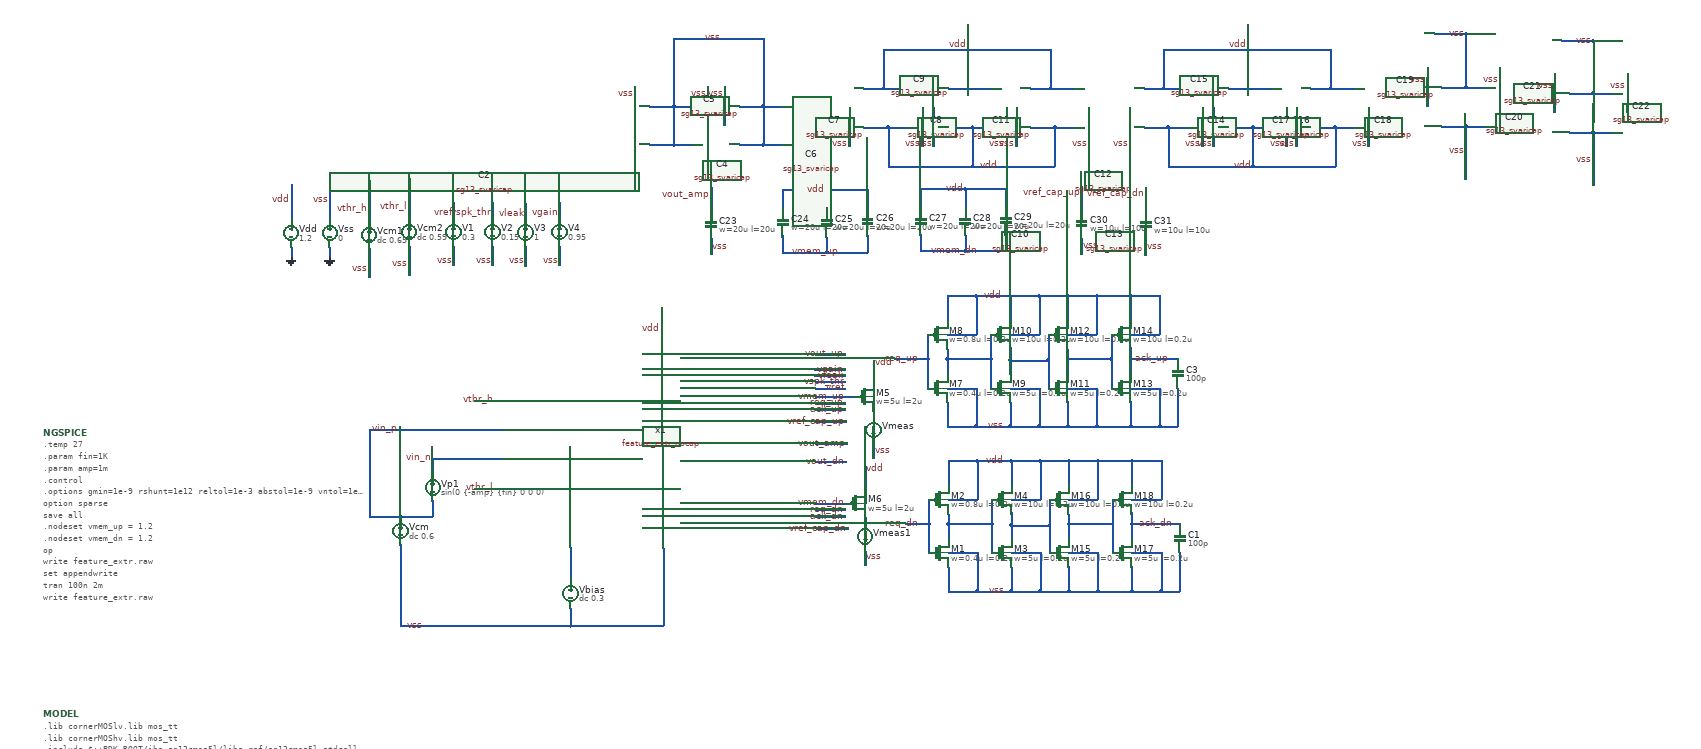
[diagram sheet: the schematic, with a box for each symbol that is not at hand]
v {xschem version=3.4.8RC file_version=1.3}
G {}
K {}
V {}
S {}
F {}
E {}
B 2 2471.25 -692.5 3271.25 -292.5 {flags=graph
y1=0.53
y2=0.74
ypos1=0
ypos2=2
divy=5
subdivy=1
unity=1
x1=0
x2=0.002
divx=5
subdivx=1
xlabmag=1.0
ylabmag=1.0
node="vout_amp
vthr_h
vthr_l
vthr
vint"
dataset=-1
unitx=1
logx=0
logy=0
rawfile=$netlist_dir/feature_extr.raw
sim_type=tran
autoload=1
color="3 7 4 12 9"
hilight_wave=2}
B 2 3291.25 -1107.5 4091.25 -707.5 {flags=graph
y1=0.0018
y2=0.21
ypos1=0
ypos2=2
divy=5
subdivy=1
unity=1
x1=0
x2=0.002
divx=5
subdivx=1
xlabmag=1.0
ylabmag=1.0
node="vout_up
vout_dn"
dataset=-1
unitx=1
logx=0
logy=0
rawfile=$netlist_dir/feature_extr.raw
sim_type=tran
autoload=1
color="4 5"
hilight_wave=1}
B 2 3291.25 -692.5 4091.25 -292.5 {flags=graph
y1=0
y2=0.01
ypos1=0
ypos2=2
divy=5
subdivy=1
unity=1
x1=0
x2=0.002
divx=5
subdivx=1
xlabmag=1.0
ylabmag=1.0
dataset=-1
unitx=1
logx=0
logy=0
sim_type=tran
autoload=1
color="5 4"
node="i(v.x1.vmeas3)
i(v.x1.vmeas1)"
hilight_wave=1}
B 2 2481.25 -222.5 3281.25 177.5 {flags=graph
y1=0.53
y2=0.74
ypos1=0
ypos2=2
divy=5
subdivy=1
unity=1
x1=0
x2=0.002
divx=5
subdivx=1
xlabmag=1.0
ylabmag=1.0
dataset=-1
unitx=1
logx=0
logy=0
rawfile=$netlist_dir/feature_extr.raw
sim_type=tran
autoload=1
color="10 7 12"
node="vout_amp
x1.net6
x1.net5"}
B 2 3303.125 -267.5 4103.125 132.5 {flags=graph
y1=0
y2=0.01
ypos1=0
ypos2=2
divy=5
subdivy=1
unity=1
x1=0
x2=0.002
divx=5
subdivx=1
xlabmag=1.0
ylabmag=1.0
dataset=-1
unitx=1
logx=0
logy=0
sim_type=tran
autoload=1
color="4 6"
node="i(v.x1.vmeas4)
i(v.x1.vmeas2)"
hilight_wave=-1}
B 2 3330 196.25 4130 596.25 {flags=graph
y1=2.2e-09
y2=6.8e-08
ypos1=0
ypos2=2
divy=5
subdivy=1
unity=1
x1=0
x2=0.002
divx=5
subdivx=1
xlabmag=1.0
ylabmag=1.0
node=i(vmeas)
dataset=-1
unitx=1
logx=0
logy=0
rawfile=$netlist_dir/feature_extr.raw
sim_type=tran
autoload=1
color=4
hilight_wave=-1}
B 2 4170 196.25 4970 596.25 {flags=graph
y1=2.1e-09
y2=3.5e-08
ypos1=0
ypos2=2
divy=5
subdivy=1
unity=1
x1=0
x2=0.002
divx=5
subdivx=1
xlabmag=1.0
ylabmag=1.0
dataset=-1
unitx=1
logx=0
logy=0
rawfile=$netlist_dir/feature_extr.raw
sim_type=tran
autoload=1
color=4
node=i(vmeas1)
hilight_wave=-1}
B 2 4108.525390625 -695.302734375 4908.525390625 -295.302734375 {flags=graph
y1=-0.004
y2=1.3
ypos1=0
ypos2=2
divy=5
subdivy=1
unity=1
x1=0
x2=0.002
divx=5
subdivx=1
xlabmag=1.0
ylabmag=1.0
node="req_up
ack_up"
dataset=-1
unitx=1
logx=0
logy=0
rawfile=$netlist_dir/feature_extr.raw
sim_type=tran
autoload=1
color="5 4"
hcursor2_y=-0.86477319
hilight_wave=0}
B 2 2471.25 -1107.5 3271.25 -707.5 {flags=graph
y1=0.59
y2=0.61
ypos1=0
ypos2=2
divy=5
subdivy=1
unity=1
x1=0
x2=0.002
divx=5
subdivx=1
xlabmag=1.0
ylabmag=1.0
node="vin_p
vin_n"
dataset=-1
unitx=1
logx=0
logy=0
rawfile=$netlist_dir/feature_extr.raw
sim_type=tran
autoload=1
color="6 3"}
B 2 4108.2275390625 -1108.84765625 4908.2275390625 -708.84765625 {flags=graph
y1=0.94
y2=1.3
ypos1=0
ypos2=2
divy=5
subdivy=1
unity=1
x1=0
x2=0.002
divx=5
subdivx=1
xlabmag=1.0
ylabmag=1.0
node="vmem_up
vmem_dn"
dataset=-1
unitx=1
logx=0
logy=0
rawfile=$netlist_dir/feature_extr.raw
sim_type=tran
autoload=1
color="5 4"
hilight_wave=-1}
B 2 4928.2275390625 -1108.84765625 5728.2275390625 -708.84765625 {flags=graph
y1=0.959568
y2=1.558848
ypos1=0
ypos2=2
divy=5
subdivy=1
unity=1
x1=0
x2=0.002
divx=5
subdivx=1
xlabmag=1.0
ylabmag=1.0
dataset=-1
unitx=1
logx=0
logy=0
rawfile=$netlist_dir/feature_extr.raw
sim_type=tran
autoload=1
hilight_wave=1
color="5 4"
node="x1.x5.vmem_d
x1.x7.vmem_d"}
B 2 4108.525390625 -265.302734375 4908.525390625 134.697265625 {flags=graph
y1=-0.0036
y2=1.3
ypos1=0
ypos2=2
divy=5
subdivy=1
unity=1
x1=0
x2=0.002
divx=5
subdivx=1
xlabmag=1.0
ylabmag=1.0
node="req_dn
ack_dn"
dataset=-1
unitx=1
logx=0
logy=0
rawfile=$netlist_dir/feature_extr.raw
sim_type=tran
autoload=1
color="4 10"
hcursor2_y=-0.86477319
hilight_wave=-1}
N 510 -1102.5 510 -1082.5 {
lab=GND}
N 590 -1102.5 590 -1082.5 {
lab=GND}
N 672.5 -727.5 947.5 -727.5 {
lab=vin_p}
N 672.5 -727.5 672.5 -547.5 {lab=vin_p}
N 736.25 -547.5 802.5 -547.5 {lab=vin_p}
N 671.25 -1240 671.25 -1157.5 {lab=vthr_h}
N 671.25 -1100 671.25 -1040 {lab=vss}
N 753.75 -1103.75 753.75 -1043.75 {lab=vss}
N 510 -1232.5 510 -1162.5 {lab=vdd}
N 590 -1232.5 590 -1162.5 {lab=vss}
N 1278.75 -482.5 1278.75 -322.5 {lab=vss}
N 888.75 -787.5 946.25 -787.5 {lab=vthr_h}
N 888.75 -606.25 947.5 -606.25 {lab=vthr_l}
N 1273.75 -977.5 1273.75 -925 {lab=vdd}
N 1591.25 -882.5 1653.75 -882.5 {lab=vout_up}
N 1591.25 -697.5 1657.5 -697.5 {lab=vout_amp}
N 1591.25 -825 1653.75 -825 {lab=vspk_thr}
N 1591.25 -812.5 1653.75 -812.5 {lab=vref}
N 1591.25 -795 1671.25 -795 {lab=vmem_up}
N 1591.25 -781.25 1653.75 -781.25 {lab=req_up}
N 1591.25 -767.5 1653.75 -767.5 {lab=ack_up}
N 1591.25 -575 1653.75 -575 {lab=vmem_dn}
N 1591.25 -561.25 1653.75 -561.25 {lab=req_dn}
N 1591.25 -547.5 1653.75 -547.5 {lab=ack_dn}
N 2301.25 -733.75 2338.75 -733.75 {lab=vss}
N 2338.75 -812.5 2338.75 -733.75 {lab=vss}
N 1865 -532.5 1865 -502.5 {lab=#net1}
N 1825 -532.5 1825 -472.5 {lab=req_dn}
N 1865 -662.5 1865 -612.5 {lab=vdd}
N 1865 -472.5 1925 -472.5 {lab=vss}
N 1865 -582.5 1925 -582.5 {lab=vdd}
N 1925 -662.5 1925 -582.5 {lab=vdd}
N 1865 -662.5 1925 -662.5 {lab=vdd}
N 1865 -532.5 1955 -532.5 {lab=#net1}
N 1865 -552.5 1865 -532.5 {lab=#net1}
N 1955 -532.5 1955 -472.5 {lab=#net1}
N 1955 -582.5 1955 -532.5 {lab=#net1}
N 1995 -662.5 1995 -612.5 {lab=vdd}
N 1995 -472.5 2055 -472.5 {lab=vss}
N 1995 -582.5 2055 -582.5 {lab=vdd}
N 2055 -662.5 2055 -582.5 {lab=vdd}
N 1995 -662.5 2055 -662.5 {lab=vdd}
N 1925 -662.5 1995 -662.5 {lab=vdd}
N 1777.5 -532.5 1825 -532.5 {lab=req_dn}
N 1825 -582.5 1825 -532.5 {lab=req_dn}
N 2055 -472.5 2055 -393.75 {lab=vss}
N 1865 -442.5 1865 -393.75 {lab=vss}
N 1925 -472.5 1925 -393.75 {lab=vss}
N 1995 -442.5 1995 -393.75 {lab=vss}
N 2303.75 -393.75 2342.5 -393.75 {lab=vss}
N 1865 -393.75 1925 -393.75 {lab=vss}
N 1925 -393.75 1995 -393.75 {lab=vss}
N 1995 -393.75 2055 -393.75 {lab=vss}
N 2342.5 -472.5 2342.5 -393.75 {lab=vss}
N 753.75 -1243.75 753.75 -1163.75 {lab=vthr_l}
N 845.390625 -1194.296875 845.390625 -1164.296875 {lab=vref}
N 845.390625 -1104.296875 845.390625 -1064.296875 {lab=vss}
N 802.5 -667.5 802.5 -637.5 {lab=vin_n}
N 802.5 -667.5 946.25 -667.5 {lab=vin_n}
N 1591.25 -660 1655 -660 {lab=vout_dn}
N 1086.25 -322.5 1278.75 -322.5 {lab=vss}
N 1086.25 -483.75 1086.25 -418.75 {lab=#net2}
N 1086.25 -358.75 1086.25 -322.5 {lab=vss}
N 736.25 -322.5 1086.25 -322.5 {lab=vss}
N 1711.25 -870 1711.25 -795 {lab=vdd}
N 1693.75 -650 1693.75 -575 {lab=vdd}
N 1711.25 -766.25 1711.25 -755 {lab=#net3}
N 1711.25 -696.25 1711.25 -667.5 {lab=vss}
N 1693.75 -546.25 1693.75 -535 {lab=#net4}
N 1693.75 -476.25 1693.75 -447.5 {lab=vss}
N 925.390625 -1194.296875 925.390625 -1164.296875 {lab=vspk_thr}
N 925.390625 -1104.296875 925.390625 -1064.296875 {lab=vss}
N 993.515625 -1193.671875 993.515625 -1163.671875 {lab=vleak}
N 993.515625 -1103.671875 993.515625 -1063.671875 {lab=vss}
N 1588.4375 -837.5 1654.0625 -837.5 {lab=vleak}
N 1063.59375 -1194.375 1063.59375 -1164.375 {lab=vgain}
N 1063.59375 -1104.375 1063.59375 -1064.375 {lab=vss}
N 1588.4375 -850 1654.0625 -850 {lab=vgain}
N 1995 -530 1995 -499.921875 {lab=#net5}
N 2241.25 -872.5 2338.75 -872.5 {lab=ack_up}
N 2113.75 -532.5 2113.75 -502.5 {lab=#net6}
N 2113.75 -662.5 2113.75 -612.5 {lab=vdd}
N 2113.75 -472.5 2173.75 -472.5 {lab=vss}
N 2113.75 -582.5 2173.75 -582.5 {lab=vdd}
N 2173.75 -662.5 2173.75 -582.5 {lab=vdd}
N 2113.75 -532.5 2203.75 -532.5 {lab=#net6}
N 2113.75 -552.5 2113.75 -532.5 {lab=#net6}
N 2203.75 -532.5 2203.75 -472.5 {lab=#net6}
N 2203.75 -582.5 2203.75 -532.5 {lab=#net6}
N 2243.75 -662.5 2243.75 -612.5 {lab=vdd}
N 2243.75 -472.5 2303.75 -472.5 {lab=vss}
N 2243.75 -582.5 2303.75 -582.5 {lab=vdd}
N 2303.75 -662.5 2303.75 -582.5 {lab=vdd}
N 2243.75 -662.5 2303.75 -662.5 {lab=vdd}
N 2173.75 -662.5 2243.75 -662.5 {lab=vdd}
N 2113.75 -662.5 2173.75 -662.5 {lab=vdd}
N 2113.75 -443.75 2113.75 -393.75 {lab=vss}
N 2243.75 -443.75 2243.75 -393.75 {lab=vss}
N 2173.75 -393.75 2243.75 -393.75 {lab=vss}
N 2073.75 -530 2073.75 -472.5 {lab=#net5}
N 2173.75 -472.5 2173.75 -393.75 {lab=vss}
N 2113.75 -393.75 2173.75 -393.75 {lab=vss}
N 2303.75 -472.5 2303.75 -393.75 {lab=vss}
N 2243.75 -393.75 2303.75 -393.75 {lab=vss}
N 2243.75 -532.5 2243.75 -499.765625 {lab=ack_dn}
N 2055 -393.75 2113.75 -393.75 {lab=vss}
N 2055 -662.5 2113.75 -662.5 {lab=vdd}
N 1995 -530 2073.75 -530 {lab=#net5}
N 1995 -555.078125 1995 -530 {lab=#net5}
N 2073.75 -582.5 2073.75 -530 {lab=#net5}
N 2243.75 -532.5 2342.5 -532.5 {lab=ack_dn}
N 2243.75 -555.078125 2243.75 -532.5 {lab=ack_dn}
N 1862.5 -872.5 1862.5 -842.5 {lab=#net7}
N 1862.5 -1002.5 1862.5 -952.5 {lab=vdd}
N 1862.5 -812.5 1922.5 -812.5 {lab=vss}
N 1862.5 -922.5 1922.5 -922.5 {lab=vdd}
N 1922.5 -1002.5 1922.5 -922.5 {lab=vdd}
N 1862.5 -1002.5 1922.5 -1002.5 {lab=vdd}
N 1862.5 -872.5 1952.5 -872.5 {lab=#net7}
N 1862.5 -892.5 1862.5 -872.5 {lab=#net7}
N 1952.5 -872.5 1952.5 -812.5 {lab=#net7}
N 1952.5 -922.5 1952.5 -872.5 {lab=#net7}
N 1992.5 -1002.5 1992.5 -952.5 {lab=vdd}
N 1992.5 -812.5 2052.5 -812.5 {lab=vss}
N 1992.5 -922.5 2052.5 -922.5 {lab=vdd}
N 2052.5 -1002.5 2052.5 -922.5 {lab=vdd}
N 1992.5 -1002.5 2052.5 -1002.5 {lab=vdd}
N 1922.5 -1002.5 1992.5 -1002.5 {lab=vdd}
N 1822.5 -872.5 1822.5 -812.5 {lab=req_up}
N 2052.5 -812.5 2052.5 -733.75 {lab=vss}
N 1862.5 -782.5 1862.5 -733.75 {lab=vss}
N 1922.5 -812.5 1922.5 -733.75 {lab=vss}
N 1992.5 -782.5 1992.5 -733.75 {lab=vss}
N 1862.5 -733.75 1922.5 -733.75 {lab=vss}
N 1922.5 -733.75 1992.5 -733.75 {lab=vss}
N 1992.5 -733.75 2052.5 -733.75 {lab=vss}
N 1992.5 -870 1992.5 -839.921875 {lab=#net8}
N 2111.25 -872.5 2111.25 -842.5 {lab=#net9}
N 2111.25 -1002.5 2111.25 -952.5 {lab=vdd}
N 2111.25 -812.5 2171.25 -812.5 {lab=vss}
N 2111.25 -922.5 2171.25 -922.5 {lab=vdd}
N 2171.25 -1002.5 2171.25 -922.5 {lab=vdd}
N 2111.25 -872.5 2201.25 -872.5 {lab=#net9}
N 2111.25 -892.5 2111.25 -872.5 {lab=#net9}
N 2201.25 -872.5 2201.25 -812.5 {lab=#net9}
N 2201.25 -922.5 2201.25 -872.5 {lab=#net9}
N 2241.25 -1002.5 2241.25 -952.5 {lab=vdd}
N 2241.25 -812.5 2301.25 -812.5 {lab=vss}
N 2241.25 -922.5 2301.25 -922.5 {lab=vdd}
N 2301.25 -1002.5 2301.25 -922.5 {lab=vdd}
N 2241.25 -1002.5 2301.25 -1002.5 {lab=vdd}
N 2171.25 -1002.5 2241.25 -1002.5 {lab=vdd}
N 2111.25 -1002.5 2171.25 -1002.5 {lab=vdd}
N 2111.25 -783.75 2111.25 -733.75 {lab=vss}
N 2241.25 -783.75 2241.25 -733.75 {lab=vss}
N 2171.25 -733.75 2241.25 -733.75 {lab=vss}
N 2071.25 -870 2071.25 -812.5 {lab=#net8}
N 2171.25 -812.5 2171.25 -733.75 {lab=vss}
N 2111.25 -733.75 2171.25 -733.75 {lab=vss}
N 2301.25 -812.5 2301.25 -733.75 {lab=vss}
N 2241.25 -733.75 2301.25 -733.75 {lab=vss}
N 2052.5 -733.75 2111.25 -733.75 {lab=vss}
N 2052.5 -1002.5 2111.25 -1002.5 {lab=vdd}
N 1992.5 -870 2071.25 -870 {lab=#net8}
N 1992.5 -895.078125 1992.5 -870 {lab=#net8}
N 2071.25 -922.5 2071.25 -870 {lab=#net8}
N 2241.25 -872.5 2241.25 -839.765625 {lab=ack_up}
N 2241.25 -895.078125 2241.25 -872.5 {lab=ack_up}
N 1755 -872.5 1822.5 -872.5 {lab=req_up}
N 1822.5 -922.5 1822.5 -872.5 {lab=req_up}
N 736.25 -490 736.25 -322.5 {lab=vss}
N 802.5 -581.25 802.5 -547.5 {lab=vin_p}
N 736.25 -547.5 736.25 -543.75 {lab=vin_p}
N 672.5 -547.5 736.25 -547.5 {lab=vin_p}
N 1590 -742.5 1656.25 -742.5 {lab=vref_cap_up}
N 1592.5 -522.5 1658.75 -522.5 {lab=vref_cap_dn}
N 1298.75 -1393.75 1338.75 -1393.75 {lab=vss}
N 1298.75 -1313.75 1338.75 -1313.75 {lab=vss}
N 1298.75 -1393.75 1298.75 -1313.75 {lab=vss}
N 1248.75 -1313.75 1298.75 -1313.75 {lab=vss}
N 1248.75 -1393.75 1298.75 -1393.75 {lab=vss}
N 1218.75 -1433.75 1218.75 -1353.75 {lab=vss}
N 1368.75 -1433.75 1368.75 -1353.75 {lab=vss}
N 1298.75 -1533.75 1298.75 -1393.75 {lab=vss}
N 1483.75 -1393.75 1523.75 -1393.75 {lab=vss}
N 1483.75 -1313.75 1523.75 -1313.75 {lab=vss}
N 1483.75 -1393.75 1483.75 -1313.75 {lab=vss}
N 1433.75 -1313.75 1483.75 -1313.75 {lab=vss}
N 1433.75 -1393.75 1483.75 -1393.75 {lab=vss}
N 1403.75 -1433.75 1403.75 -1353.75 {lab=vss}
N 1483.75 -1533.75 1483.75 -1393.75 {lab=vss}
N 1298.75 -1533.75 1483.75 -1533.75 {lab=vss}
N 1741.25 -1350 1781.25 -1350 {lab=vdd}
N 1741.25 -1350 1741.25 -1270 {lab=vdd}
N 1691.25 -1350 1741.25 -1350 {lab=vdd}
N 1731.25 -1430 1781.25 -1430 {lab=vdd}
N 1661.25 -1390 1661.25 -1310 {lab=vss}
N 1811.25 -1390 1811.25 -1310 {lab=vss}
N 1731.25 -1510 1731.25 -1430 {lab=vdd}
N 1691.25 -1430 1731.25 -1430 {lab=vdd}
N 1915 -1350 1955 -1350 {lab=vdd}
N 1915 -1350 1915 -1270 {lab=vdd}
N 1865 -1350 1915 -1350 {lab=vdd}
N 1905 -1430 1955 -1430 {lab=vdd}
N 1835 -1390 1835 -1310 {lab=vss}
N 1985 -1390 1985 -1310 {lab=vss}
N 1905 -1510 1905 -1430 {lab=vdd}
N 1865 -1430 1905 -1430 {lab=vdd}
N 2085 -1350 2125 -1350 {lab=vdd}
N 2085 -1350 2085 -1270 {lab=vdd}
N 2035 -1350 2085 -1350 {lab=vdd}
N 2075 -1430 2125 -1430 {lab=vdd}
N 2005 -1390 2005 -1310 {lab=vss}
N 2155 -1390 2155 -1310 {lab=vss}
N 2075 -1510 2075 -1430 {lab=vdd}
N 2035 -1430 2075 -1430 {lab=vdd}
N 1905 -1510 2075 -1510 {lab=vdd}
N 1731.25 -1510 1905 -1510 {lab=vdd}
N 2318.75 -1350 2358.75 -1350 {lab=vdd}
N 2318.75 -1350 2318.75 -1270 {lab=vdd}
N 2268.75 -1350 2318.75 -1350 {lab=vdd}
N 2308.75 -1430 2358.75 -1430 {lab=vdd}
N 2238.75 -1390 2238.75 -1310 {lab=vss}
N 2388.75 -1390 2388.75 -1310 {lab=vss}
N 2308.75 -1510 2308.75 -1430 {lab=vdd}
N 2268.75 -1430 2308.75 -1430 {lab=vdd}
N 2492.5 -1350 2532.5 -1350 {lab=vdd}
N 2492.5 -1350 2492.5 -1270 {lab=vdd}
N 2442.5 -1350 2492.5 -1350 {lab=vdd}
N 2482.5 -1430 2532.5 -1430 {lab=vdd}
N 2412.5 -1390 2412.5 -1310 {lab=vss}
N 2562.5 -1390 2562.5 -1310 {lab=vss}
N 2482.5 -1510 2482.5 -1430 {lab=vdd}
N 2442.5 -1430 2482.5 -1430 {lab=vdd}
N 2662.5 -1350 2702.5 -1350 {lab=vdd}
N 2662.5 -1350 2662.5 -1270 {lab=vdd}
N 2612.5 -1350 2662.5 -1350 {lab=vdd}
N 2652.5 -1430 2702.5 -1430 {lab=vdd}
N 2582.5 -1390 2582.5 -1310 {lab=vss}
N 2732.5 -1390 2732.5 -1310 {lab=vss}
N 2652.5 -1510 2652.5 -1430 {lab=vdd}
N 2612.5 -1430 2652.5 -1430 {lab=vdd}
N 2482.5 -1510 2652.5 -1510 {lab=vdd}
N 2308.75 -1510 2482.5 -1510 {lab=vdd}
N 1905 -1562.5 1905 -1510 {lab=vdd}
N 2482.5 -1562.5 2482.5 -1510 {lab=vdd}
N 1915 -1270 2085 -1270 {lab=vdd}
N 2492.5 -1270 2662.5 -1270 {lab=vdd}
N 2318.75 -1270 2492.5 -1270 {lab=vdd}
N 2932.5 -1432.5 2972.5 -1432.5 {lab=vss}
N 2932.5 -1352.5 2972.5 -1352.5 {lab=vss}
N 2882.5 -1432.5 2932.5 -1432.5 {lab=vss}
N 2852.5 -1472.5 2852.5 -1392.5 {lab=vss}
N 3002.5 -1472.5 3002.5 -1392.5 {lab=vss}
N 2932.5 -1542.5 2932.5 -1432.5 {lab=vss}
N 2932.5 -1352.5 2932.5 -1242.5 {lab=vss}
N 2882.5 -1352.5 2932.5 -1352.5 {lab=vss}
N 1741.25 -1270 1915 -1270 {lab=vdd}
N 3195 -1420 3235 -1420 {lab=vss}
N 3195 -1340 3235 -1340 {lab=vss}
N 3145 -1420 3195 -1420 {lab=vss}
N 3115 -1460 3115 -1380 {lab=vss}
N 3265 -1460 3265 -1380 {lab=vss}
N 3195 -1528.75 3195 -1420 {lab=vss}
N 3195 -1340 3195 -1230 {lab=vss}
N 3145 -1340 3195 -1340 {lab=vss}
N 2932.5 -1542.5 2933.75 -1542.5 {lab=vss}
N 2867.5 -1542.5 2932.5 -1542.5 {lab=vss}
N 3195 -1528.75 3196.25 -1528.75 {lab=vss}
N 3130 -1528.75 3195 -1528.75 {lab=vss}
N 3195 -1530 3195 -1528.75 {lab=vss}
N 1376.25 -1226.25 1376.25 -1180 {lab=vout_amp}
N 1376.25 -1120 1376.25 -1087.5 {lab=vss}
N 1523.75 -1126.25 1523.75 -1092.5 {lab=vmem_up}
N 1698.75 -1126.25 1698.75 -1092.5 {lab=vmem_up}
N 1615 -1092.5 1698.75 -1092.5 {lab=vmem_up}
N 1615 -1123.75 1615 -1092.5 {lab=vmem_up}
N 1523.75 -1092.5 1615 -1092.5 {lab=vmem_up}
N 1523.75 -1221.25 1523.75 -1183.75 {lab=vdd}
N 1698.75 -1221.25 1698.75 -1185 {lab=vdd}
N 1615 -1221.25 1698.75 -1221.25 {lab=vdd}
N 1615 -1221.25 1615 -1183.75 {lab=vdd}
N 1523.75 -1221.25 1615 -1221.25 {lab=vdd}
N 1808.75 -1128.75 1808.75 -1095 {lab=vmem_dn}
N 1983.75 -1128.75 1983.75 -1095 {lab=vmem_dn}
N 1900 -1095 1983.75 -1095 {lab=vmem_dn}
N 1900 -1126.25 1900 -1095 {lab=vmem_dn}
N 1808.75 -1095 1900 -1095 {lab=vmem_dn}
N 1808.75 -1223.75 1808.75 -1186.25 {lab=vdd}
N 1983.75 -1223.75 1983.75 -1187.5 {lab=vdd}
N 1900 -1223.75 1983.75 -1223.75 {lab=vdd}
N 1900 -1223.75 1900 -1186.25 {lab=vdd}
N 1808.75 -1223.75 1900 -1223.75 {lab=vdd}
N 2140 -1227.5 2140 -1181.25 {lab=vref_cap_up}
N 2140 -1121.25 2140 -1088.75 {lab=vss}
N 2272.5 -1225 2272.5 -1178.75 {lab=vref_cap_dn}
N 2272.5 -1118.75 2272.5 -1086.25 {lab=vss}
C {devices/vsource.sym} 510 -1132.5 0 0 {name=Vdd value=1.2}
C {devices/gnd.sym} 510 -1082.5 0 0 {name=l3 lab=GND}
C {devices/launcher.sym} 560 -140 0 0 {name=h2
descr="simulate" 
tclcommand="xschem save; xschem netlist; xschem simulate"
}
C {devices/launcher.sym} 800 -140 0 0 {name=h3
descr="annotate OP" 
tclcommand="set show_hidden_texts 1; xschem annotate_op"
}
C {devices/vsource.sym} 590 -1132.5 0 0 {name=Vss value=0}
C {devices/gnd.sym} 590 -1082.5 0 0 {name=l1 lab=GND}
C {devices/vsource.sym} 736.25 -517.5 0 0 {name=Vcm value="dc 0.6"}
C {devices/lab_wire.sym} 732.5 -727.5 0 0 {name=p4 sig_type=std_logic lab=vin_p}
C {devices/lab_wire.sym} 802.5 -667.5 0 0 {name=p7 sig_type=std_logic lab=vin_n}
C {devices/vsource.sym} 802.5 -607.5 0 0 {name=Vp1 value="sin(0 \{-amp\} \{fin\} 0 0 0)"}
C {devices/code_shown.sym} 0 -720 0 0 {name=NGSPICE only_toplevel=true 
value="
.temp 27
.param fin=1K
.param amp=1m
.control
.options gmin=1e-9 rshunt=1e12 reltol=1e-3 abstol=1e-9 vntol=1e-6

option sparse
save all

.nodeset vmem_up = 1.2
.nodeset vmem_dn = 1.2
op
write feature_extr.raw
set appendwrite

tran 100n 2m
write feature_extr.raw
wrdata amplification.csv vin_p vin_n vout_amp
wrdata comparison.csv vout_up vout_dn vthr_h vthr_l i(v.x1.vmeas1) i(v.x1.vmeas3)
wrdata event_conversion.csv req_up req_dn vmem_up vmem_dn


plot v(req_up) v(req_dn)
plot v(vmem_up) v(vmem_dn)


.endc
"}
C {devices/code_shown.sym} 0 -140 0 0 {name=MODEL only_toplevel=true
format="tcleval( @value )"
value="
.lib cornerMOSlv.lib mos_tt
.lib cornerMOShv.lib mos_tt
.include $::PDK_ROOT/ihp-sg13cmos5l/libs.ref/sg13cmos5l_stdcell/spice/sg13cmos5l_stdcell.spice
.include $::PDK_ROOT/ihp-sg13cmos5l/libs.tech/ngspice/models/cap_mfringe.lib
"}
C {devices/title.sym} 160 0 0 0 {name=l5 author="(c) 2024-2025 Harald Pretl, Apache-2.0 license"}
C {devices/vsource.sym} 671.25 -1127.5 0 0 {name=Vcm1 value="dc 0.65"}
C {devices/vsource.sym} 753.75 -1133.75 0 0 {name=Vcm2 value="dc 0.59"}
C {devices/lab_wire.sym} 1806.25 -872.5 0 0 {name=p32 sig_type=std_logic lab=req_up}
C {capa.sym} 2338.75 -842.5 0 0 {name=C3
m=1
value=100p
footprint=1206
device="ceramic capacitor"}
C {lab_wire.sym} 931.25 -787.5 0 0 {name=p6 sig_type=std_logic lab=vthr_h}
C {lab_wire.sym} 931.25 -606.25 0 0 {name=p8 sig_type=std_logic lab=vthr_l}
C {lab_wire.sym} 1273.75 -935 1 0 {name=p9 sig_type=std_logic lab=vdd}
C {lab_wire.sym} 1652.5 -882.5 0 0 {name=p11 sig_type=std_logic lab=vout_up}
C {lab_wire.sym} 1656.25 -697.5 0 0 {name=p12 sig_type=std_logic lab=vout_amp}
C {lab_wire.sym} 1655 -660 0 0 {name=p13 sig_type=std_logic lab=vout_dn}
C {lab_wire.sym} 1653.75 -825 0 0 {name=p16 sig_type=std_logic lab=vspk_thr}
C {lab_wire.sym} 1653.75 -812.5 0 0 {name=p19 sig_type=std_logic lab=vref}
C {lab_wire.sym} 1652.5 -781.25 0 0 {name=p20 sig_type=std_logic lab=req_up}
C {lab_wire.sym} 1653.75 -795 0 0 {name=p22 sig_type=std_logic lab=vmem_up}
C {lab_wire.sym} 1652.5 -767.5 0 0 {name=p23 sig_type=std_logic lab=ack_up}
C {lab_wire.sym} 1652.5 -561.25 0 0 {name=p24 sig_type=std_logic lab=req_dn}
C {lab_wire.sym} 1653.75 -575 0 0 {name=p25 sig_type=std_logic lab=vmem_dn}
C {lab_wire.sym} 1652.5 -547.5 0 0 {name=p26 sig_type=std_logic lab=ack_dn}
C {sg13g2_pr/sg13_lv_nmos.sym} 1845 -472.5 0 0 {name=M1
l=0.2u
w=0.4u
ng=1
m=1
model=sg13_lv_nmos
spiceprefix=X
}
C {sg13g2_pr/sg13_lv_pmos.sym} 1845 -582.5 0 0 {name=M2
l=0.2u
w=0.8u
ng=1
m=1
model=sg13_lv_pmos
spiceprefix=X
}
C {sg13g2_pr/sg13_lv_nmos.sym} 1975 -472.5 0 0 {name=M3
l=0.2u
w=5u
ng=1
m=1
model=sg13_lv_nmos
spiceprefix=X
}
C {sg13g2_pr/sg13_lv_pmos.sym} 1975 -582.5 0 0 {name=M4
l=0.2u
w=10u
ng=1
m=1
model=sg13_lv_pmos
spiceprefix=X
}
C {devices/lab_wire.sym} 1807.5 -532.5 0 0 {name=p29 sig_type=std_logic lab=req_dn}
C {capa.sym} 2342.5 -502.5 0 0 {name=C1
m=1
value=100p
footprint=1206
device="ceramic capacitor"}
C {vsource.sym} 845.390625 -1134.296875 0 0 {name=V1 value=0.3 savecurrent=false}
C {devices/lab_wire.sym} 845.390625 -1173.046875 1 0 {name=p36 sig_type=std_logic lab=vref}
C {noconn.sym} 1652.5 -882.5 2 0 {name=l2}
C {noconn.sym} 1655 -660 2 0 {name=l7}
C {devices/vsource.sym} 1086.25 -388.75 0 0 {name=Vbias value="dc 0.3"}
C {lab_wire.sym} 510 -1200 1 0 {name=p1 sig_type=std_logic lab=vdd}
C {lab_wire.sym} 590 -1200 1 0 {name=p2 sig_type=std_logic lab=vss}
C {lab_wire.sym} 671.25 -1058.75 1 0 {name=p5 sig_type=std_logic lab=vss}
C {lab_wire.sym} 753.75 -1067.5 1 0 {name=p17 sig_type=std_logic lab=vss}
C {lab_wire.sym} 671.25 -1182.5 1 0 {name=p18 sig_type=std_logic lab=vthr_h}
C {lab_wire.sym} 753.75 -1185 1 0 {name=p10 sig_type=std_logic lab=vthr_l}
C {lab_wire.sym} 746.25 -322.5 2 0 {name=p21 sig_type=std_logic lab=vss}
C {lab_wire.sym} 1940 -662.5 2 0 {name=p27 sig_type=std_logic lab=vdd}
C {lab_wire.sym} 1947.5 -393.75 2 0 {name=p31 sig_type=std_logic lab=vss}
C {lab_wire.sym} 845.390625 -1074.296875 1 0 {name=p38 sig_type=std_logic lab=vss}
C {sg13cmos5l_pr/sg13_lv_pmos.sym} 1691.25 -795 0 0 {name=M5
l=2u
w=5u
ng=4
m=2
model=sg13_lv_pmos
spiceprefix=X
}
C {sg13cmos5l_pr/sg13_lv_pmos.sym} 1673.75 -575 0 0 {name=M6
l=2u
w=5u
ng=4
m=2
model=sg13_lv_pmos
spiceprefix=X
}
C {lab_wire.sym} 1711.25 -863.75 2 0 {name=p39 sig_type=std_logic lab=vdd}
C {lab_wire.sym} 1693.75 -645 2 0 {name=p41 sig_type=std_logic lab=vdd}
C {ammeter.sym} 1711.25 -726.25 0 0 {name=Vmeas savecurrent=true spice_ignore=0}
C {lab_wire.sym} 1711.25 -683.75 2 0 {name=p42 sig_type=std_logic lab=vss}
C {ammeter.sym} 1693.75 -506.25 0 0 {name=Vmeas1 savecurrent=true spice_ignore=0}
C {lab_wire.sym} 1693.75 -463.75 2 0 {name=p43 sig_type=std_logic lab=vss}
C {vsource.sym} 925.390625 -1134.296875 0 0 {name=V2 value=0.15 avecurrent=false}
C {devices/lab_wire.sym} 925.390625 -1173.046875 1 0 {name=p44 sig_type=std_logic lab=vspk_thr}
C {lab_wire.sym} 925.390625 -1074.296875 1 0 {name=p45 sig_type=std_logic lab=vss}
C {vsource.sym} 993.515625 -1133.671875 0 0 {name=V3 value=1 savecurrent=false}
C {devices/lab_wire.sym} 993.515625 -1172.421875 1 0 {name=p40 sig_type=std_logic lab=vleak}
C {lab_wire.sym} 993.515625 -1073.671875 1 0 {name=p46 sig_type=std_logic lab=vss}
C {feature_extr_nocap.sym} 1272.5 -702.5 0 0 {name=x1}
C {lab_wire.sym} 1653.125 -837.5 0 0 {name=p15 sig_type=std_logic lab=vleak}
C {vsource.sym} 1063.59375 -1134.375 0 0 {name=V4 value=0.95 savecurrent=false}
C {devices/lab_wire.sym} 1063.59375 -1173.125 1 0 {name=p33 sig_type=std_logic lab=vgain}
C {lab_wire.sym} 1063.59375 -1074.375 1 0 {name=p34 sig_type=std_logic lab=vss}
C {lab_wire.sym} 1653.125 -850 0 0 {name=p35 sig_type=std_logic lab=vgain}
C {sg13g2_pr/sg13_lv_nmos.sym} 2093.75 -472.5 0 0 {name=M15
l=0.2u
w=5u
ng=1
m=1
model=sg13_lv_nmos
spiceprefix=X
}
C {sg13g2_pr/sg13_lv_pmos.sym} 2093.75 -582.5 0 0 {name=M16
l=0.2u
w=10u
ng=1
m=1
model=sg13_lv_pmos
spiceprefix=X
}
C {sg13g2_pr/sg13_lv_nmos.sym} 2223.75 -472.5 0 0 {name=M17
l=0.2u
w=5u
ng=1
m=1
model=sg13_lv_nmos
spiceprefix=X
}
C {sg13g2_pr/sg13_lv_pmos.sym} 2223.75 -582.5 0 0 {name=M18
l=0.2u
w=10u
ng=1
m=1
model=sg13_lv_pmos
spiceprefix=X
}
C {lab_wire.sym} 2331.25 -532.5 0 0 {name=p37 sig_type=std_logic lab=ack_dn}
C {lab_wire.sym} 2322.5 -872.5 0 0 {name=p47 sig_type=std_logic lab=ack_up}
C {sg13g2_pr/sg13_lv_nmos.sym} 1842.5 -812.5 0 0 {name=M7
l=0.2u
w=0.4u
ng=1
m=1
model=sg13_lv_nmos
spiceprefix=X
}
C {sg13g2_pr/sg13_lv_pmos.sym} 1842.5 -922.5 0 0 {name=M8
l=0.2u
w=0.8u
ng=1
m=1
model=sg13_lv_pmos
spiceprefix=X
}
C {sg13g2_pr/sg13_lv_nmos.sym} 1972.5 -812.5 0 0 {name=M9
l=0.2u
w=5u
ng=1
m=1
model=sg13_lv_nmos
spiceprefix=X
}
C {sg13g2_pr/sg13_lv_pmos.sym} 1972.5 -922.5 0 0 {name=M10
l=0.2u
w=10u
ng=1
m=1
model=sg13_lv_pmos
spiceprefix=X
}
C {lab_wire.sym} 1937.5 -1002.5 2 0 {name=p3 sig_type=std_logic lab=vdd}
C {lab_wire.sym} 1945 -733.75 2 0 {name=p14 sig_type=std_logic lab=vss}
C {sg13g2_pr/sg13_lv_nmos.sym} 2091.25 -812.5 0 0 {name=M11
l=0.2u
w=5u
ng=1
m=1
model=sg13_lv_nmos
spiceprefix=X
}
C {sg13g2_pr/sg13_lv_pmos.sym} 2091.25 -922.5 0 0 {name=M12
l=0.2u
w=10u
ng=1
m=1
model=sg13_lv_pmos
spiceprefix=X
}
C {sg13g2_pr/sg13_lv_nmos.sym} 2221.25 -812.5 0 0 {name=M13
l=0.2u
w=5u
ng=1
m=1
model=sg13_lv_nmos
spiceprefix=X
}
C {sg13g2_pr/sg13_lv_pmos.sym} 2221.25 -922.5 0 0 {name=M14
l=0.2u
w=10u
ng=1
m=1
model=sg13_lv_pmos
spiceprefix=X
}
C {lab_wire.sym} 1655 -742.5 0 0 {name=p28 sig_type=std_logic lab=vref_cap_up}
C {lab_wire.sym} 1657.5 -522.5 0 0 {name=p30 sig_type=std_logic lab=vref_cap_dn}
C {sg13cmos5l_pr/sg13_svaricap.sym} 1248.75 -1353.75 3 1 {name=C2 
model=sg13_hv_svaricap 
w=9.74u 
l=0.8u 
Nx=10 
body=sub!
spiceprefix=X
}
C {sg13cmos5l_pr/sg13_svaricap.sym} 1338.75 -1353.75 1 0 {name=C4 
model=sg13_hv_svaricap 
w=9.74u 
l=0.8u 
Nx=10 
body=sub!
spiceprefix=X
}
C {devices/lab_wire.sym} 1218.75 -1418.75 1 1 {name=p48 sig_type=std_logic lab=vss}
C {devices/lab_wire.sym} 1368.75 -1418.75 1 1 {name=p49 sig_type=std_logic lab=vss}
C {sg13cmos5l_pr/sg13_svaricap.sym} 1433.75 -1353.75 3 1 {name=C5 
model=sg13_hv_svaricap 
w=9.74u 
l=0.8u 
Nx=10 
body=sub!
spiceprefix=X
}
C {sg13cmos5l_pr/sg13_svaricap.sym} 1523.75 -1353.75 1 0 {name=C6 
model=sg13_hv_svaricap 
w=9.74u 
l=0.8u 
Nx=10 
body=sub!
spiceprefix=X
}
C {devices/lab_wire.sym} 1403.75 -1418.75 1 1 {name=p50 sig_type=std_logic lab=vss}
C {sg13cmos5l_pr/sg13_svaricap.sym} 1691.25 -1390 3 0 {name=C7 
model=sg13_hv_svaricap 
w=9.74u 
l=0.8u 
Nx=10 
body=sub!
spiceprefix=X
}
C {sg13cmos5l_pr/sg13_svaricap.sym} 1781.25 -1390 1 1 {name=C8 
model=sg13_hv_svaricap 
w=9.74u 
l=0.8u 
Nx=10 
body=sub!
spiceprefix=X
}
C {devices/lab_wire.sym} 1661.25 -1315 1 0 {name=p52 sig_type=std_logic lab=vss}
C {devices/lab_wire.sym} 1811.25 -1315 1 0 {name=p53 sig_type=std_logic lab=vss}
C {sg13cmos5l_pr/sg13_svaricap.sym} 1865 -1390 3 0 {name=C9 
model=sg13_hv_svaricap 
w=9.74u 
l=0.8u 
Nx=10 
body=sub!
spiceprefix=X
}
C {sg13cmos5l_pr/sg13_svaricap.sym} 1955 -1390 1 1 {name=C10 
model=sg13_hv_svaricap 
w=9.74u 
l=0.8u 
Nx=10 
body=sub!
spiceprefix=X
}
C {devices/lab_wire.sym} 1835 -1315 1 0 {name=p54 sig_type=std_logic lab=vss}
C {devices/lab_wire.sym} 1985 -1315 1 0 {name=p55 sig_type=std_logic lab=vss}
C {sg13cmos5l_pr/sg13_svaricap.sym} 2035 -1390 3 0 {name=C11 
model=sg13_hv_svaricap 
w=9.74u 
l=0.8u 
Nx=10 
body=sub!
spiceprefix=X
}
C {sg13cmos5l_pr/sg13_svaricap.sym} 2125 -1390 1 1 {name=C12 
model=sg13_hv_svaricap 
w=9.74u 
l=0.8u 
Nx=10 
body=sub!
spiceprefix=X
}
C {devices/lab_wire.sym} 2005 -1315 1 0 {name=p56 sig_type=std_logic lab=vss}
C {devices/lab_wire.sym} 2155 -1315 1 0 {name=p57 sig_type=std_logic lab=vss}
C {sg13cmos5l_pr/sg13_svaricap.sym} 2268.75 -1390 3 0 {name=C13 
model=sg13_hv_svaricap 
w=9.74u 
l=0.8u 
Nx=10 
body=sub!
spiceprefix=X
}
C {sg13cmos5l_pr/sg13_svaricap.sym} 2358.75 -1390 1 1 {name=C14 
model=sg13_hv_svaricap 
w=9.74u 
l=0.8u 
Nx=10 
body=sub!
spiceprefix=X
}
C {devices/lab_wire.sym} 2238.75 -1315 1 0 {name=p58 sig_type=std_logic lab=vss}
C {devices/lab_wire.sym} 2388.75 -1315 1 0 {name=p59 sig_type=std_logic lab=vss}
C {sg13cmos5l_pr/sg13_svaricap.sym} 2442.5 -1390 3 0 {name=C15 
model=sg13_hv_svaricap 
w=9.74u 
l=0.8u 
Nx=10 
body=sub!
spiceprefix=X
}
C {sg13cmos5l_pr/sg13_svaricap.sym} 2532.5 -1390 1 1 {name=C16 
model=sg13_hv_svaricap 
w=9.74u 
l=0.8u 
Nx=10 
body=sub!
spiceprefix=X
}
C {devices/lab_wire.sym} 2412.5 -1315 1 0 {name=p60 sig_type=std_logic lab=vss}
C {devices/lab_wire.sym} 2562.5 -1315 1 0 {name=p61 sig_type=std_logic lab=vss}
C {sg13cmos5l_pr/sg13_svaricap.sym} 2612.5 -1390 3 0 {name=C17 
model=sg13_hv_svaricap 
w=9.74u 
l=0.8u 
Nx=10 
body=sub!
spiceprefix=X
}
C {sg13cmos5l_pr/sg13_svaricap.sym} 2702.5 -1390 1 1 {name=C18 
model=sg13_hv_svaricap 
w=9.74u 
l=0.8u 
Nx=10 
body=sub!
spiceprefix=X
}
C {devices/lab_wire.sym} 2582.5 -1315 1 0 {name=p62 sig_type=std_logic lab=vss}
C {devices/lab_wire.sym} 2732.5 -1315 1 0 {name=p63 sig_type=std_logic lab=vss}
C {lab_wire.sym} 1905 -1520 1 0 {name=p64 sig_type=std_logic lab=vdd}
C {lab_wire.sym} 2482.5 -1520 1 0 {name=p65 sig_type=std_logic lab=vdd}
C {lab_wire.sym} 1970 -1270 0 0 {name=p66 sig_type=std_logic lab=vdd}
C {lab_wire.sym} 2492.5 -1270 0 0 {name=p67 sig_type=std_logic lab=vdd}
C {sg13cmos5l_pr/sg13_svaricap.sym} 2882.5 -1392.5 3 1 {name=C19 
model=sg13_hv_svaricap 
w=9.74u 
l=0.8u 
Nx=5 
body=sub!
spiceprefix=X
}
C {sg13cmos5l_pr/sg13_svaricap.sym} 2972.5 -1392.5 1 0 {name=C20 
model=sg13_hv_svaricap 
w=9.74u 
l=0.8u 
Nx=5 
body=sub!
spiceprefix=X
}
C {devices/lab_wire.sym} 3002.5 -1447.5 1 0 {name=p68 sig_type=std_logic lab=vss}
C {devices/lab_wire.sym} 2852.5 -1447.5 1 0 {name=p69 sig_type=std_logic lab=vss}
C {sg13cmos5l_pr/sg13_svaricap.sym} 3145 -1380 3 1 {name=C21 
model=sg13_hv_svaricap 
w=9.74u 
l=0.8u 
Nx=5 
body=sub!
spiceprefix=X
}
C {sg13cmos5l_pr/sg13_svaricap.sym} 3235 -1380 1 0 {name=C22 
model=sg13_hv_svaricap 
w=9.74u 
l=0.8u 
Nx=5 
body=sub!
spiceprefix=X
}
C {devices/lab_wire.sym} 3265 -1435 1 0 {name=p70 sig_type=std_logic lab=vss}
C {devices/lab_wire.sym} 3115 -1435 1 0 {name=p71 sig_type=std_logic lab=vss}
C {devices/lab_wire.sym} 2932.5 -1301.25 1 1 {name=p72 sig_type=std_logic lab=vss}
C {devices/lab_wire.sym} 3195 -1283.75 1 1 {name=p73 sig_type=std_logic lab=vss}
C {lab_wire.sym} 2932.5 -1542.5 0 0 {name=p74 sig_type=std_logic lab=vss}
C {lab_wire.sym} 3195 -1528.75 0 0 {name=p75 sig_type=std_logic lab=vss}
C {sg13cmos5l_pr/cap_mfringe.sym} 1376.25 -1150 0 0 {name=C23
model=cap_mfringe
w=20u
l=20u
mmin=1
mmax=4
spiceprefix=X
}
C {lab_wire.sym} 1376.25 -1103.75 2 0 {name=p76 sig_type=std_logic lab=vss}
C {lab_wire.sym} 1376.25 -1210 0 0 {name=p77 sig_type=std_logic lab=vout_amp}
C {devices/lab_wire.sym} 1397.5 -1533.75 2 1 {name=p51 sig_type=std_logic lab=vss}
C {sg13cmos5l_pr/cap_mfringe.sym} 1523.75 -1153.75 0 0 {name=C24
model=cap_mfringe
w=20u
l=20u
mmin=1
mmax=4
spiceprefix=X
}
C {sg13cmos5l_pr/cap_mfringe.sym} 1615 -1153.75 0 0 {name=C25
model=cap_mfringe
w=20u
l=20u
mmin=1
mmax=4
spiceprefix=X
}
C {sg13cmos5l_pr/cap_mfringe.sym} 1698.75 -1155 0 0 {name=C26
model=cap_mfringe
w=20u
l=20u
mmin=1
mmax=4
spiceprefix=X
}
C {lab_wire.sym} 1642.5 -1092.5 0 0 {name=p78 sig_type=std_logic lab=vmem_up}
C {lab_wire.sym} 1572.5 -1221.25 2 0 {name=p79 sig_type=std_logic lab=vdd}
C {sg13cmos5l_pr/cap_mfringe.sym} 1808.75 -1156.25 0 0 {name=C27
model=cap_mfringe
w=20u
l=20u
mmin=1
mmax=4
spiceprefix=X
}
C {sg13cmos5l_pr/cap_mfringe.sym} 1900 -1156.25 0 0 {name=C28
model=cap_mfringe
w=20u
l=20u
mmin=1
mmax=4
spiceprefix=X
}
C {sg13cmos5l_pr/cap_mfringe.sym} 1983.75 -1157.5 0 0 {name=C29
model=cap_mfringe
w=20u
l=20u
mmin=1
mmax=4
spiceprefix=X
}
C {lab_wire.sym} 1927.5 -1095 0 0 {name=p80 sig_type=std_logic lab=vmem_dn}
C {lab_wire.sym} 1857.5 -1223.75 2 0 {name=p81 sig_type=std_logic lab=vdd}
C {sg13cmos5l_pr/cap_mfringe.sym} 2140 -1151.25 0 0 {name=C30
model=cap_mfringe
w=10u
l=10u
mmin=1
mmax=4
spiceprefix=X
}
C {lab_wire.sym} 2140 -1105 2 0 {name=p82 sig_type=std_logic lab=vss}
C {sg13cmos5l_pr/cap_mfringe.sym} 2272.5 -1148.75 0 0 {name=C31
model=cap_mfringe
w=10u
l=10u
mmin=1
mmax=4
spiceprefix=X
}
C {lab_wire.sym} 2272.5 -1102.5 2 0 {name=p84 sig_type=std_logic lab=vss}
C {lab_wire.sym} 2140 -1215 0 0 {name=p83 sig_type=std_logic lab=vref_cap_up}
C {lab_wire.sym} 2272.5 -1212.5 0 0 {name=p85 sig_type=std_logic lab=vref_cap_dn}
